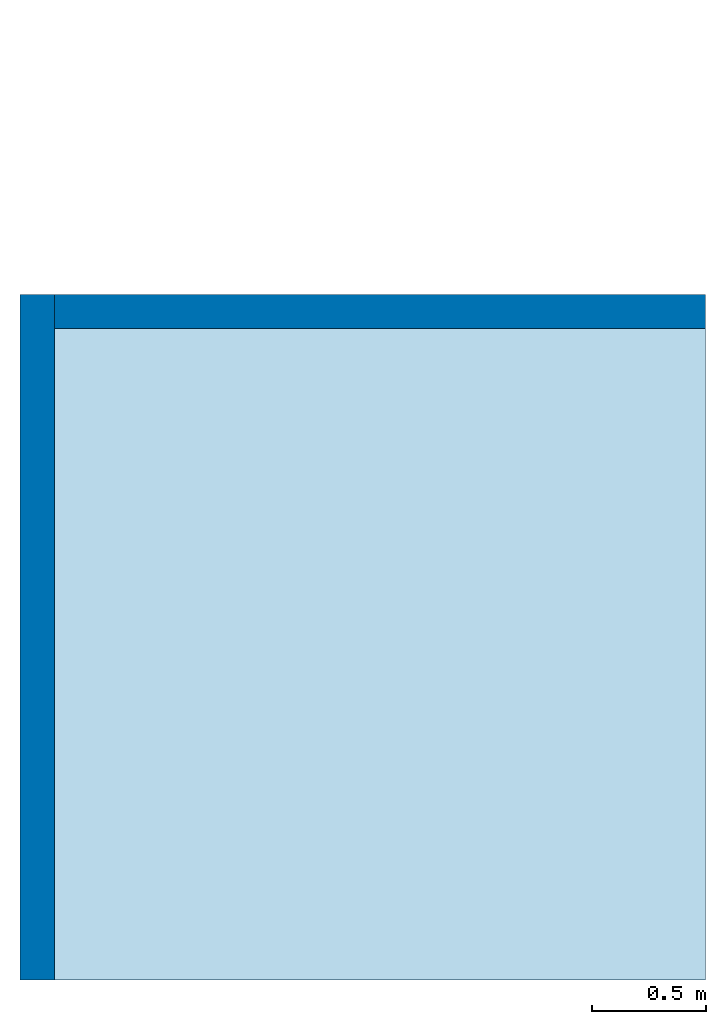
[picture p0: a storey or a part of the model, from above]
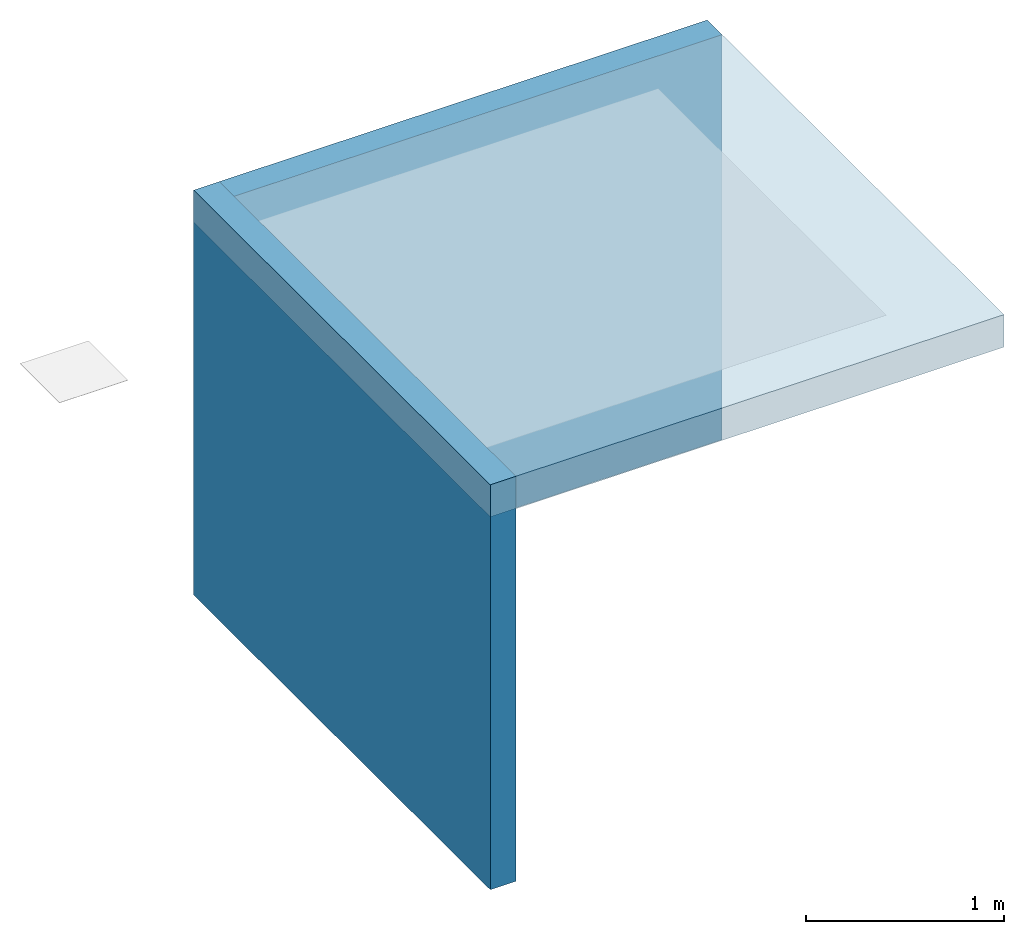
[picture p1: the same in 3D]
Properties of the parts of a building model (IFC2X3)

# File
Description: ViewDefinition [CoordinationView_V2.0], RevitIdentifiers [VersionGUID: 03acd572-c6cd-4f49-8667-6e8432f69d16, NumberOfSaves: 18], CoordinateReference [CoordinateBase: Coordenadas compartilhadas]
File name: 0001
Time: 2025-02-06T11:37:25
Written by: ODA IFC SDK 22.8
Made in: 22.1.50.17 - Exporter 22.6.2.0 - IU alternativa 22.6.2.0

# IfcProject, 0001
LongName: Teto de áreas sujeitas à vapor - Membrana de Poliuretano VITPOLI ECO; Phase: Status do projeto

# IfcSite, Default
RefLatitude: 42, 21, 31, 181944; RefLongitude: -71, -3, -24, -263304; RefElevation: 0 m

# IfcBuilding
Pset_BuildingCommon - NumberOfStoreys: 1; IsLandmarked: no

# IfcBuildingStorey: Nível:Cabeça de 8 mm, ARQ Térreo
LongName: ARQ Térreo; Elevation: -0.0025238 m

# IfcBuildingElementProxy: IMPER:IMPER:433934, IMPER:IMPER:433934:IMPER:433934 : IMPER:IMPER:433934:291594
In: ARQ Térreo
Type - Material: #Vitpoli Eco, #Primer
Type - Pset_BuildingElementProxyCommon - Reference: IMPER
Type - Pset_QuantityTakeOff - Reference: IMPER
Type - Pset_ProvisionForVoid - Width: 0.952886 m; Height: 0.00103887 m; Depth: 2.76 m
Pset_BuildingElementProxyCommon - sets with these values: 2

# IfcCovering: Forro composto:IMPT - VITPOLI ECO, Forro composto:IMPT - VITPOLI ECO:301707
In: ARQ Térreo
Type - PredefinedType: CEILING
Type - Pset_CoveringCommon - TotalThickness: 0.002 m
Material: #Primer 0.001 m, #Vitpoli Eco 0.001 m
Pset_CoveringCommon - Reference: IMPT - VITPOLI ECO; Finish: #Vitpoli Eco;
Pset_QuantityTakeOff - Reference: IMPT - VITPOLI ECO

# IfcSlab: Piso:Piso:LAJE CONCRETO, Piso:Piso:LAJE CONCRETO:293951
In: ARQ Térreo
Type - PredefinedType: FLOOR; Material: #concreto 0.2 m
Type - Pset_SlabCommon - IsExternal: no
Pset_QuantityTakeOff - Reference: Piso:LAJE CONCRETO; sets with these values: 2
Pset_SlabCommon - Reference: Piso:LAJE CONCRETO; LoadBearing: no; PitchAngle: 0 deg

# IfcWallStandardCase: Parede básica:Parede básica:Parede Concreto (2)
In: ARQ Térreo
Type - PredefinedType: STANDARD; Material: #concreto 0.15 m
Type - Pset_WallCommon - IsExternal: yes; ThermalTransmittance: 6.97333 kg/K/s3
Pset_QuantityTakeOff - Reference: Parede Concreto; sets with these values: 2
Pset_WallCommon - LoadBearing: no; Reference: Parede Concreto; ExtendToStructure: no
